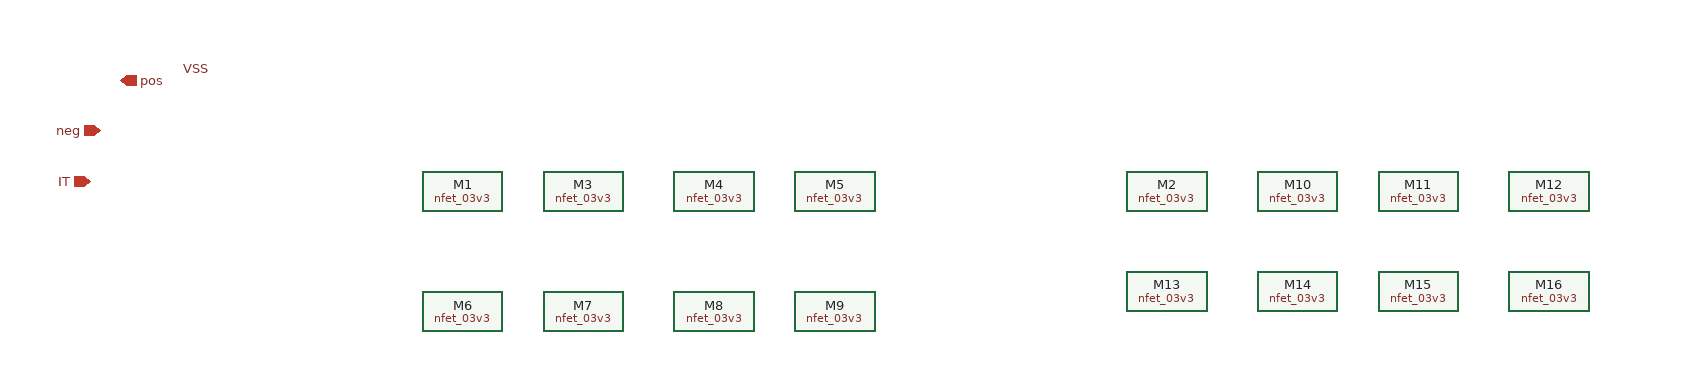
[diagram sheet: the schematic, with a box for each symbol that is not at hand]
v {xschem version=3.4.5 file_version=1.2
}
G {}
K {}
V {}
S {}
E {}
C {devices/lab_wire.sym} -90 -230 0 0 {name=p9 sig_type=std_logic lab=VSS}
C {devices/iopin.sym} -210 -120 0 0 {name=p3 lab=IT}
C {devices/iopin.sym} -200 -170 0 0 {name=p2 lab=neg}
C {devices/iopin.sym} -180 -220 0 1 {name=p1 lab=pos}
C {symbols/nfet_03v3.sym} 160 -110 0 0 {name=M1
L=2u
W=2u
nf=1
m=1
ad="'int((nf+1)/2) * W/nf * 0.18u'"
pd="'2*int((nf+1)/2) * (W/nf + 0.18u)'"
as="'int((nf+2)/2) * W/nf * 0.18u'"
ps="'2*int((nf+2)/2) * (W/nf + 0.18u)'"
nrd="'0.18u / W'" nrs="'0.18u / W'"
sa=0 sb=0 sd=0
model=nfet_03v3
spiceprefix=X
}
C {symbols/nfet_03v3.sym} 860 -110 0 1 {name=M2
L=2u
W=2u
nf=1
m=1
ad="'int((nf+1)/2) * W/nf * 0.18u'"
pd="'2*int((nf+1)/2) * (W/nf + 0.18u)'"
as="'int((nf+2)/2) * W/nf * 0.18u'"
ps="'2*int((nf+2)/2) * (W/nf + 0.18u)'"
nrd="'0.18u / W'" nrs="'0.18u / W'"
sa=0 sb=0 sd=0
model=nfet_03v3
spiceprefix=X
}
C {symbols/nfet_03v3.sym} 280 -110 0 0 {name=M3
L=2u
W=2u
nf=1
m=1
ad="'int((nf+1)/2) * W/nf * 0.18u'"
pd="'2*int((nf+1)/2) * (W/nf + 0.18u)'"
as="'int((nf+2)/2) * W/nf * 0.18u'"
ps="'2*int((nf+2)/2) * (W/nf + 0.18u)'"
nrd="'0.18u / W'" nrs="'0.18u / W'"
sa=0 sb=0 sd=0
model=nfet_03v3
spiceprefix=X
}
C {symbols/nfet_03v3.sym} 410 -110 0 0 {name=M4
L=2u
W=2u
nf=1
m=1
ad="'int((nf+1)/2) * W/nf * 0.18u'"
pd="'2*int((nf+1)/2) * (W/nf + 0.18u)'"
as="'int((nf+2)/2) * W/nf * 0.18u'"
ps="'2*int((nf+2)/2) * (W/nf + 0.18u)'"
nrd="'0.18u / W'" nrs="'0.18u / W'"
sa=0 sb=0 sd=0
model=nfet_03v3
spiceprefix=X
}
C {symbols/nfet_03v3.sym} 530 -110 0 0 {name=M5
L=2u
W=2u
nf=1
m=1
ad="'int((nf+1)/2) * W/nf * 0.18u'"
pd="'2*int((nf+1)/2) * (W/nf + 0.18u)'"
as="'int((nf+2)/2) * W/nf * 0.18u'"
ps="'2*int((nf+2)/2) * (W/nf + 0.18u)'"
nrd="'0.18u / W'" nrs="'0.18u / W'"
sa=0 sb=0 sd=0
model=nfet_03v3
spiceprefix=X
}
C {symbols/nfet_03v3.sym} 160 10 0 0 {name=M6
L=2u
W=2u
nf=1
m=1
ad="'int((nf+1)/2) * W/nf * 0.18u'"
pd="'2*int((nf+1)/2) * (W/nf + 0.18u)'"
as="'int((nf+2)/2) * W/nf * 0.18u'"
ps="'2*int((nf+2)/2) * (W/nf + 0.18u)'"
nrd="'0.18u / W'" nrs="'0.18u / W'"
sa=0 sb=0 sd=0
model=nfet_03v3
spiceprefix=X
}
C {symbols/nfet_03v3.sym} 280 10 0 0 {name=M7
L=2u
W=2u
nf=1
m=1
ad="'int((nf+1)/2) * W/nf * 0.18u'"
pd="'2*int((nf+1)/2) * (W/nf + 0.18u)'"
as="'int((nf+2)/2) * W/nf * 0.18u'"
ps="'2*int((nf+2)/2) * (W/nf + 0.18u)'"
nrd="'0.18u / W'" nrs="'0.18u / W'"
sa=0 sb=0 sd=0
model=nfet_03v3
spiceprefix=X
}
C {symbols/nfet_03v3.sym} 410 10 0 0 {name=M8
L=2u
W=2u
nf=1
m=1
ad="'int((nf+1)/2) * W/nf * 0.18u'"
pd="'2*int((nf+1)/2) * (W/nf + 0.18u)'"
as="'int((nf+2)/2) * W/nf * 0.18u'"
ps="'2*int((nf+2)/2) * (W/nf + 0.18u)'"
nrd="'0.18u / W'" nrs="'0.18u / W'"
sa=0 sb=0 sd=0
model=nfet_03v3
spiceprefix=X
}
C {symbols/nfet_03v3.sym} 530 10 0 0 {name=M9
L=2u
W=2u
nf=1
m=1
ad="'int((nf+1)/2) * W/nf * 0.18u'"
pd="'2*int((nf+1)/2) * (W/nf + 0.18u)'"
as="'int((nf+2)/2) * W/nf * 0.18u'"
ps="'2*int((nf+2)/2) * (W/nf + 0.18u)'"
nrd="'0.18u / W'" nrs="'0.18u / W'"
sa=0 sb=0 sd=0
model=nfet_03v3
spiceprefix=X
}
C {symbols/nfet_03v3.sym} 990 -110 0 1 {name=M10
L=2u
W=2u
nf=1
m=1
ad="'int((nf+1)/2) * W/nf * 0.18u'"
pd="'2*int((nf+1)/2) * (W/nf + 0.18u)'"
as="'int((nf+2)/2) * W/nf * 0.18u'"
ps="'2*int((nf+2)/2) * (W/nf + 0.18u)'"
nrd="'0.18u / W'" nrs="'0.18u / W'"
sa=0 sb=0 sd=0
model=nfet_03v3
spiceprefix=X
}
C {symbols/nfet_03v3.sym} 1110 -110 0 1 {name=M11
L=2u
W=2u
nf=1
m=1
ad="'int((nf+1)/2) * W/nf * 0.18u'"
pd="'2*int((nf+1)/2) * (W/nf + 0.18u)'"
as="'int((nf+2)/2) * W/nf * 0.18u'"
ps="'2*int((nf+2)/2) * (W/nf + 0.18u)'"
nrd="'0.18u / W'" nrs="'0.18u / W'"
sa=0 sb=0 sd=0
model=nfet_03v3
spiceprefix=X
}
C {symbols/nfet_03v3.sym} 1240 -110 0 1 {name=M12
L=2u
W=2u
nf=1
m=1
ad="'int((nf+1)/2) * W/nf * 0.18u'"
pd="'2*int((nf+1)/2) * (W/nf + 0.18u)'"
as="'int((nf+2)/2) * W/nf * 0.18u'"
ps="'2*int((nf+2)/2) * (W/nf + 0.18u)'"
nrd="'0.18u / W'" nrs="'0.18u / W'"
sa=0 sb=0 sd=0
model=nfet_03v3
spiceprefix=X
}
C {symbols/nfet_03v3.sym} 860 -10 0 1 {name=M13
L=2u
W=2u
nf=1
m=1
ad="'int((nf+1)/2) * W/nf * 0.18u'"
pd="'2*int((nf+1)/2) * (W/nf + 0.18u)'"
as="'int((nf+2)/2) * W/nf * 0.18u'"
ps="'2*int((nf+2)/2) * (W/nf + 0.18u)'"
nrd="'0.18u / W'" nrs="'0.18u / W'"
sa=0 sb=0 sd=0
model=nfet_03v3
spiceprefix=X
}
C {symbols/nfet_03v3.sym} 990 -10 0 1 {name=M14
L=2u
W=2u
nf=1
m=1
ad="'int((nf+1)/2) * W/nf * 0.18u'"
pd="'2*int((nf+1)/2) * (W/nf + 0.18u)'"
as="'int((nf+2)/2) * W/nf * 0.18u'"
ps="'2*int((nf+2)/2) * (W/nf + 0.18u)'"
nrd="'0.18u / W'" nrs="'0.18u / W'"
sa=0 sb=0 sd=0
model=nfet_03v3
spiceprefix=X
}
C {symbols/nfet_03v3.sym} 1110 -10 0 1 {name=M15
L=2u
W=2u
nf=1
m=1
ad="'int((nf+1)/2) * W/nf * 0.18u'"
pd="'2*int((nf+1)/2) * (W/nf + 0.18u)'"
as="'int((nf+2)/2) * W/nf * 0.18u'"
ps="'2*int((nf+2)/2) * (W/nf + 0.18u)'"
nrd="'0.18u / W'" nrs="'0.18u / W'"
sa=0 sb=0 sd=0
model=nfet_03v3
spiceprefix=X
}
C {symbols/nfet_03v3.sym} 1240 -10 0 1 {name=M16
L=2u
W=2u
nf=1
m=1
ad="'int((nf+1)/2) * W/nf * 0.18u'"
pd="'2*int((nf+1)/2) * (W/nf + 0.18u)'"
as="'int((nf+2)/2) * W/nf * 0.18u'"
ps="'2*int((nf+2)/2) * (W/nf + 0.18u)'"
nrd="'0.18u / W'" nrs="'0.18u / W'"
sa=0 sb=0 sd=0
model=nfet_03v3
spiceprefix=X
}
